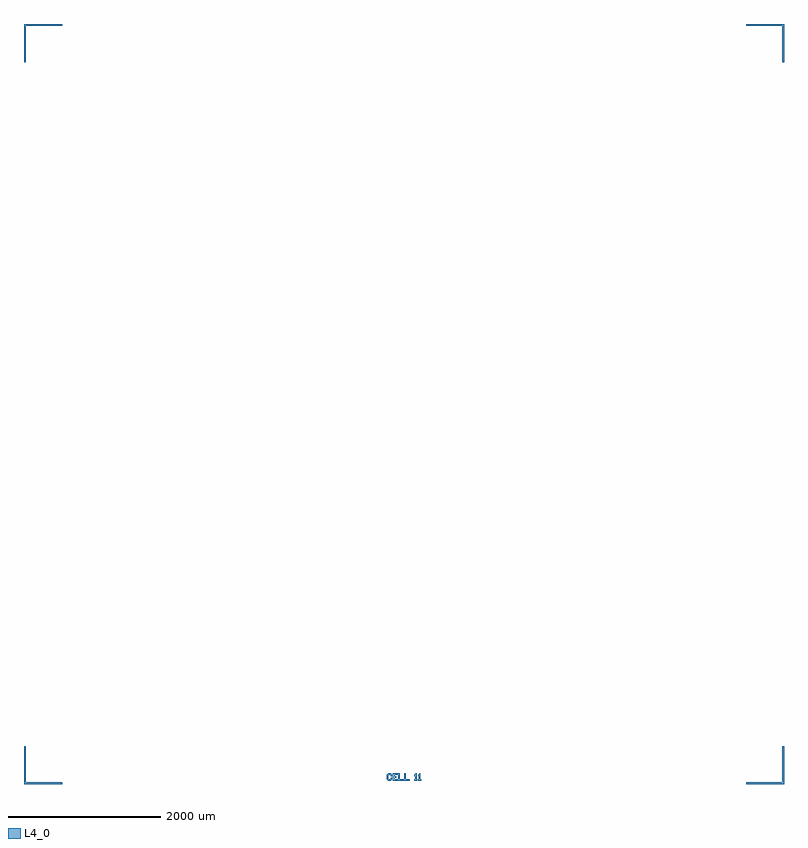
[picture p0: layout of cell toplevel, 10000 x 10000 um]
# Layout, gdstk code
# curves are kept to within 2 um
import gdstk
lib = gdstk.Library(unit=1e-6, precision=1e-09)
def P(c, l, *ps):  # polygons
    for p in ps: c.add(gdstk.Polygon(p, *l))
L4_0 = (4, 0)

toplevel = lib.new_cell('toplevel')
P(toplevel, L4_0, [(5000,5000),(5000,4500),(4980,4500),(4980,4980),(4500,4980),(4500,5000)],
  [(-5000,5000),(-5000,4500),(-4980,4500),(-4980,4980),(-4500,4980),(-4500,5000)],
  [(5000,-5000),(5000,-4500),(4980,-4500),(4980,-4980),(4500,-4980),(4500,-5000)],
  [(-5000,-5000),(-5000,-4500),(-4980,-4500),(-4980,-4980),(-4500,-4980),(-4500,-5000)],
  [(-205,-4960),(-225,-4940),(-225,-4880),(-205,-4860),(-175,-4860),(-155,-4880),(-155,-4900),(-175,-4900),(-175,-4890),(-185,-4880),(-195,-4880),(-205,-4890),(-205,-4930),(-195,-4940),(-185,-4940),(-175,-4930),(-175,-4920),(-155,-4920),(-155,-4940),(-175,-4960)],
  [(-85,-4860),(-85,-4880),(-125,-4880),(-125,-4900),(-105,-4900),(-105,-4920),(-125,-4920),(-125,-4940),(-85,-4940),(-85,-4960),(-145,-4960),(-145,-4860),(-85,-4860)],
  [(-75,-4860),(-55,-4860),(-55,-4940),(-5,-4940),(-5,-4960),(-75,-4960),(-75,-4860)],
  [(5,-4860),(25,-4860),(25,-4940),(75,-4940),(75,-4960),(5,-4960),(5,-4860)],
  [(145,-4900),(135,-4900),(135,-4880),(155,-4860),(165,-4860),(165,-4940),(175,-4940),(175,-4960),(135,-4960),(135,-4940),(145,-4940)],
  [(195,-4900),(185,-4900),(185,-4880),(205,-4860),(215,-4860),(215,-4940),(225,-4940),(225,-4960),(185,-4960),(185,-4940),(195,-4940)])

lib.write_gds('toplevel.gds')
